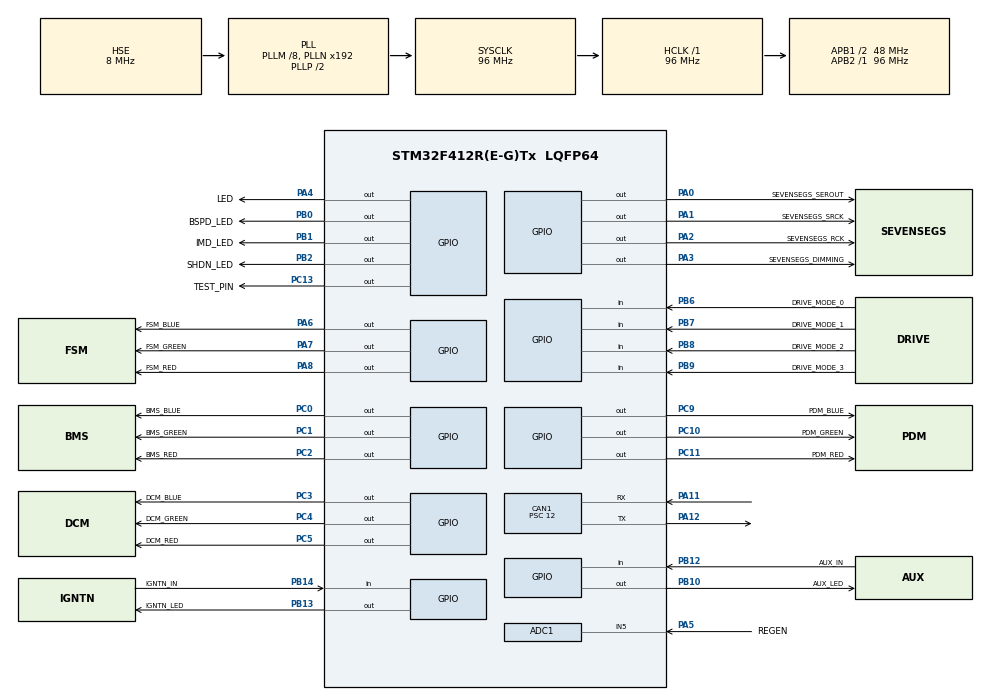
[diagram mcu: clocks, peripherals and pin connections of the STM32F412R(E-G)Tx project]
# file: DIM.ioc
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ADC1.Channel-0\#ChannelRegularConversion=ADC_CHANNEL_5
ADC1.NbrOfConversionFlag=1
ADC1.Rank-0\#ChannelRegularConversion=1
ADC1.SamplingTime-0\#ChannelRegularConversion=ADC_SAMPLETIME_3CYCLES
ADC1.master=1
CAN1.ABOM=ENABLE
CAN1.BS1=CAN_BS1_6TQ
CAN1.CalculateTimeQuantum=250.0
CAN1.NART=ENABLE
CAN1.Prescaler=12
CAN1.RFLM=ENABLE
CAN1.SJW=CAN_SJW_4TQ
CAN1.TXFP=ENABLE
Dma.ADC1.0.Direction=DMA_PERIPH_TO_MEMORY
Dma.ADC1.0.FIFOMode=DMA_FIFOMODE_DISABLE
Dma.ADC1.0.Instance=DMA2_Stream0
Dma.ADC1.0.MemDataAlignment=DMA_MDATAALIGN_HALFWORD
Dma.ADC1.0.MemInc=DMA_MINC_ENABLE
Dma.ADC1.0.Mode=DMA_NORMAL
Dma.ADC1.0.PeriphDataAlignment=DMA_PDATAALIGN_HALFWORD
Dma.ADC1.0.PeriphInc=DMA_PINC_DISABLE
Dma.ADC1.0.Priority=DMA_PRIORITY_LOW
Dma.Request0=ADC1
FREERTOS.INCLUDE_vTaskDelayUntil=1
FREERTOS.MEMORY_ALLOCATION=1
FREERTOS.Tasks01=Task100Hz,-1,512,RunTask100Hz,Default,NULL,Static,Task100HzBuffer,Task100HzControlBlock;TaskCanRx,-3,512,RunTaskCanRx,Default,NULL,Static,TaskCanRxBuffer,TaskCanRxControlBlock;TaskCanTx,-3,512,RunTaskCanTx,Default,NULL,Static,TaskCanTxBuffer,TaskCanTxControlBlock;Task1kHz,0,512,RunTask1kHz,Default,NULL,Static,Task1kHzBuffer,Task1kHzControlBlock;Task1Hz,-2,512,RunTask1Hz,Default,NULL,Static,Task1HzBuffer,Task1HzControlBlock
FREERTOS.configCHECK_FOR_STACK_OVERFLOW=2
FREERTOS.configRECORD_STACK_HIGH_ADDRESS=0
FREERTOS.configUSE_TASK_NOTIFICATIONS=1
FREERTOS.configUSE_TICK_HOOK=1
FREERTOS.configUSE_TRACE_FACILITY=1
IWDG.Reload=LSI_FREQUENCY /  IWDG_PRESCALER / IWDG_RESET_FREQUENCY
Mcu.Family=STM32F4
Mcu.Name=STM32F412R(E-G)Tx
Mcu.Package=LQFP64
Mcu.UserConstants=LSI_FREQUENCY,32000;IWDG_PRESCALER,4;IWDG_RESET_FREQUENCY,5
NVIC.CAN1_RX0_IRQn=true\:5\:0\:false\:false\:true\:true\:true\:true
NVIC.CAN1_RX1_IRQn=true\:5\:0\:false\:false\:true\:true\:true\:true
NVIC.DMA2_Stream0_IRQn=true\:5\:0\:false\:false\:true\:true\:false\:true
NVIC.PriorityGroup=NVIC_PRIORITYGROUP_4
NVIC.TIM6_IRQn=true\:0\:0\:false\:false\:true\:false\:false\:true
NVIC.TimeBase=TIM6_IRQn
NVIC.TimeBaseIP=TIM6
PA0.GPIO_Label=SEVENSEGS_SEROUT
PA0.GPIO_Speed=GPIO_SPEED_FREQ_VERY_HIGH
PA0.PinState=GPIO_PIN_RESET
PA0.Signal=GPIO_Output
PA1.GPIO_Label=SEVENSEGS_SRCK
PA1.GPIO_Speed=GPIO_SPEED_FREQ_VERY_HIGH
PA1.PinState=GPIO_PIN_RESET
PA1.Signal=GPIO_Output
PA11.Mode=Master
PA11.Signal=CAN1_RX
PA12.Mode=Master
PA12.Signal=CAN1_TX
PA13.Mode=Trace_Asynchronous_SW
PA13.Signal=SYS_JTMS-SWDIO
PA14.Mode=Trace_Asynchronous_SW
PA14.Signal=SYS_JTCK-SWCLK
PA2.GPIO_Label=SEVENSEGS_RCK
PA2.GPIO_Speed=GPIO_SPEED_FREQ_VERY_HIGH
PA2.PinState=GPIO_PIN_RESET
PA2.Signal=GPIO_Output
PA3.GPIO_Label=SEVENSEGS_DIMMING
PA3.GPIO_Speed=GPIO_SPEED_FREQ_LOW
PA3.PinState=GPIO_PIN_RESET
PA3.Signal=GPIO_Output
PA4.GPIO_Label=LED
PA4.Signal=GPIO_Output
PA5.GPIO_Label=REGEN
PA5.Signal=SharedAnalog_PA5
PA6.GPIO_Label=FSM_BLUE
PA6.Signal=GPIO_Output
PA7.GPIO_Label=FSM_GREEN
PA7.Signal=GPIO_Output
PA8.GPIO_Label=FSM_RED
PA8.Signal=GPIO_Output
PB0.GPIO_Label=BSPD_LED
PB0.Signal=GPIO_Output
PB1.GPIO_Label=IMD_LED
PB1.Signal=GPIO_Output
PB10.GPIO_Label=AUX_LED
PB10.Signal=GPIO_Output
PB12.GPIO_Label=AUX_IN
PB12.GPIO_PuPd=GPIO_PULLUP
PB12.Signal=GPIO_Input
PB13.GPIO_Label=IGNTN_LED
PB13.Signal=GPIO_Output
PB14.GPIO_Label=IGNTN_IN
PB14.GPIO_PuPd=GPIO_PULLUP
PB14.Signal=GPIO_Input
PB2.GPIO_Label=SHDN_LED
PB2.Signal=GPIO_Output
PB3.Mode=Trace_Asynchronous_SW
PB3.Signal=SYS_JTDO-SWO
PB6.GPIO_Label=DRIVE_MODE_0
PB6.Signal=GPIO_Input
PB7.GPIO_Label=DRIVE_MODE_1
PB7.Signal=GPIO_Input
PB8.GPIO_Label=DRIVE_MODE_2
PB8.Signal=GPIO_Input
PB9.GPIO_Label=DRIVE_MODE_3
PB9.Signal=GPIO_Input
PC0.GPIO_Label=BMS_BLUE
PC0.Signal=GPIO_Output
PC1.GPIO_Label=BMS_GREEN
PC1.Signal=GPIO_Output
PC10.GPIO_Label=PDM_GREEN
PC10.Signal=GPIO_Output
PC11.GPIO_Label=PDM_RED
PC11.Signal=GPIO_Output
PC13.GPIO_Label=TEST_PIN
PC13.PinState=GPIO_PIN_SET
PC13.Signal=GPIO_Output
PC2.GPIO_Label=BMS_RED
PC2.Signal=GPIO_Output
PC3.GPIO_Label=DCM_BLUE
PC3.Signal=GPIO_Output
PC4.GPIO_Label=DCM_GREEN
PC4.Signal=GPIO_Output
PC5.GPIO_Label=DCM_RED
PC5.Signal=GPIO_Output
PC9.GPIO_Label=PDM_BLUE
PC9.Signal=GPIO_Output
PH0\ -\ OSC_IN.Mode=HSE-External-Oscillator
PH0\ -\ OSC_IN.Signal=RCC_OSC_IN
PH1\ -\ OSC_OUT.Mode=HSE-External-Oscillator
PH1\ -\ OSC_OUT.Signal=RCC_OSC_OUT
ProjectManager.HeapSize=0X00
ProjectManager.StackSize=0x400
ProjectManager.TargetToolchain=SW4STM32
RCC.AHBFreq_Value=96000000
RCC.APB1CLKDivider=RCC_HCLK_DIV2
RCC.APB1Freq_Value=48000000
RCC.APB1TimFreq_Value=96000000
RCC.APB2Freq_Value=96000000
RCC.APB2TimFreq_Value=96000000
RCC.CortexFreq_Value=96000000
RCC.HCLKFreq_Value=96000000
RCC.HSE_VALUE=8000000
RCC.PLLM=8
RCC.PLLSourceVirtual=RCC_PLLSOURCE_HSE
RCC.SYSCLKFreq_VALUE=96000000
RCC.SYSCLKSource=RCC_SYSCLKSOURCE_PLLCLK
RCC.USBFreq_Value=96000000
RCC.VCOOutputFreq_Value=192000000
SH.SharedAnalog_PA5.0=GPIO_Analog
SH.SharedAnalog_PA5.1=ADC1_IN5,IN5
VP_FREERTOS_VS_CMSIS_V1.Mode=CMSIS_V1
VP_IWDG_VS_IWDG.Mode=IWDG_Activate
VP_SYS_VS_tim6.Mode=TIM6
board=custom

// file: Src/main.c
/* USER CODE BEGIN Header */
/**
 ******************************************************************************
 * @file           : main.c
 * @brief          : Main program body
 ******************************************************************************
 * @attention
 *
 * <h2><center>&copy; Copyright (c) 2020 STMicroelectronics.
 * All rights reserved.</center></h2>
 *
 * This software component is licensed by ST under BSD 3-Clause license,
 * the "License"; You may not use this file except in compliance with the
 * License. You may obtain a copy of the License at:
 *                        opensource.org/licenses/BSD-3-Clause
 *
 ******************************************************************************
 */
/* USER CODE END Header */

#include "main.h"
#include "cmsis_os.h"

/* USER CODE BEGIN Includes */
#include <assert.h>

#include "App_DimWorld.h"
#include "App_SharedMacros.h"
#include "App_SevenSegDisplay.h"
#include "App_SharedStateMachine.h"
#include "states/App_DriveState.h"
#include "configs/App_RotarySwitchConfig.h"
#include "configs/App_HeartbeatMonitorConfig.h"
#include "App_CanAlerts.h"

#include "Io_CanTx.h"
#include "Io_CanRx.h"
#include "Io_SoftwareWatchdog.h"
#include "Io_StackWaterMark.h"
#include "Io_SevenSegDisplays.h"
#include "Io_SharedCan.h"
#include "Io_SharedErrorHandlerOverride.h"
#include "Io_SharedHardFaultHandler.h"
#include "Io_SharedHeartbeatMonitor.h"
#include "Io_RgbLedSequence.h"
#include "Io_DriveModeSwitch.h"
#include "Io_Leds.h"
#include "Io_Switches.h"
#include "Io_Adc.h"
#include "Io_RgbLeds.h"
/* USER CODE END Includes */

ADC_HandleTypeDef hadc1;
DMA_HandleTypeDef hdma_adc1;

CAN_HandleTypeDef hcan1;

IWDG_HandleTypeDef hiwdg;

osThreadId          Task100HzHandle;
uint32_t            Task100HzBuffer[512];
osStaticThreadDef_t Task100HzControlBlock;
osThreadId          TaskCanRxHandle;
uint32_t            TaskCanRxBuffer[512];
osStaticThreadDef_t TaskCanRxControlBlock;
osThreadId          TaskCanTxHandle;
uint32_t            TaskCanTxBuffer[512];
osStaticThreadDef_t TaskCanTxControlBlock;
osThreadId          Task1kHzHandle;
uint32_t            Task1kHzBuffer[512];
osStaticThreadDef_t Task1kHzControlBlock;
osThreadId          Task1HzHandle;
uint32_t            Task1HzBuffer[512];
osStaticThreadDef_t Task1HzControlBlock;
/* USER CODE BEGIN PV */
struct DimWorld *         world;
struct StateMachine *     state_machine;
struct DimCanTxInterface *can_tx;
struct DimCanRxInterface *can_rx;
struct SevenSegDisplay *  left_seven_seg_display;
struct SevenSegDisplay *  middle_seven_seg_display;
struct SevenSegDisplay *  right_seven_seg_display;
struct SevenSegDisplays * seven_seg_displays;
struct HeartbeatMonitor * heartbeat_monitor;
struct RgbLedSequence *   rgb_led_sequence;
struct RotarySwitch *     drive_mode_switch;
struct Led *              imd_led;
struct Led *              bspd_led;
struct BinarySwitch *     start_switch;
struct BinarySwitch *     aux_switch;
struct RgbLed *           bms_status_led;
struct RgbLed *           dcm_status_led;
struct RgbLed *           dim_status_led;
struct RgbLed *           fsm_status_led;
struct RgbLed *           pdm_status_led;
struct Clock *            clock;
/* USER CODE END PV */

void        SystemClock_Config(void);
static void MX_GPIO_Init(void);
static void MX_DMA_Init(void);
static void MX_ADC1_Init(void);
static void MX_CAN1_Init(void);
static void MX_IWDG_Init(void);
void        RunTask100Hz(void const *argument);
void        RunTaskCanRx(void const *argument);
void        RunTaskCanTx(void const *argument);
void        RunTask1kHz(void const *argument);
void        RunTask1Hz(void const *argument);

/* USER CODE BEGIN 0 */
static void CanRxQueueOverflowCallBack(size_t overflow_count)
{
    App_CanTx_DIM_Errors_RxOverflowCount_Set(overflow_count);
}

static void CanTxQueueOverflowCallBack(size_t overflow_count)
{
    App_CanTx_DIM_Errors_TxOverflowCount_Set(overflow_count);
}
/* USER CODE END 0 */

int main(void)
{

    /* MCU Configuration--------------------------------------------------------*/

    /* Reset of all peripherals, Initializes the Flash interface and the Systick. */
    HAL_Init();

    /* Configure the system clock */
    SystemClock_Config();

    /* Initialize all configured peripherals */
    MX_GPIO_Init();
    MX_DMA_Init();
    MX_ADC1_Init();
    MX_CAN1_Init();
    MX_IWDG_Init();
    /* USER CODE BEGIN 2 */
    __HAL_DBGMCU_FREEZE_IWDG();

    HAL_ADC_Start_DMA(&hadc1, (uint32_t *)Io_Adc_GetRawAdcValues(), hadc1.Init.NbrOfConversion);
    //    HAL_TIM_Base_Start(&htim2); // TODO: May need to enable this for DMA for ADC

    Io_SharedHardFaultHandler_Init();
    Io_SharedSoftwareWatchdog_Init(Io_HardwareWatchdog_Refresh, Io_SoftwareWatchdog_TimeoutCallback);
    Io_SharedCan_Init(&hcan1, CanTxQueueOverflowCallBack, CanRxQueueOverflowCallBack);
    Io_CanTx_EnableMode(CAN_MODE_DEFAULT, true);
    Io_SevenSegDisplays_Init();

    App_CanTx_Init();
    App_CanRx_Init();
    App_CanAlerts_Init(Io_CanTx_DIM_Alerts_SendAperiodic);

    left_seven_seg_display   = App_SevenSegDisplay_Create(Io_SevenSegDisplays_SetLeftHexDigit);
    middle_seven_seg_display = App_SevenSegDisplay_Create(Io_SevenSegDisplays_SetMiddleHexDigit);
    right_seven_seg_display  = App_SevenSegDisplay_Create(Io_SevenSegDisplays_SetRightHexDigit);

    seven_seg_displays = App_SevenSegDisplays_Create(
        left_seven_seg_display, middle_seven_seg_display, right_seven_seg_display, Io_SevenSegDisplays_WriteCommands);

    heartbeat_monitor = App_SharedHeartbeatMonitor_Create(
        Io_SharedHeartbeatMonitor_GetCurrentMs, HEARTBEAT_MONITOR_TIMEOUT_PERIOD_MS, HEARTBEAT_MONITOR_BOARDS_TO_CHECK);

    rgb_led_sequence = App_SharedRgbLedSequence_Create(
        Io_RgbLedSequence_TurnOnRedLed, Io_RgbLedSequence_TurnOnBlueLed, Io_RgbLedSequence_TurnOnGreenLed);

    drive_mode_switch = App_RotarySwitch_Create(Io_DriveModeSwitch_GetPosition, NUM_DRIVE_MODE_SWITCH_POSITIONS);

    imd_led = App_Led_Create(Io_Leds_TurnOnImdLed, Io_Leds_TurnOffImdLed);

    bspd_led = App_Led_Create(Io_Leds_TurnOnBspdLed, Io_Leds_TurnOffBspdLed);

    start_switch = App_BinarySwitch_Create(Io_Switches_StartSwitchIsTurnedOn);

    aux_switch = App_BinarySwitch_Create(Io_Switches_AuxSwitchIsTurnedOn);

    bms_status_led = App_SharedRgbLed_Create(
        Io_RgbLeds_TurnBmsStatusLedRed, Io_RgbLeds_TurnBmsStatusLedGreen, Io_RgbLeds_TurnBmsStatusLedBlue,
        Io_RgbLeds_TurnOffBmsStatusLed);

    dcm_status_led = App_SharedRgbLed_Create(
        Io_RgbLeds_TurnDcmStatusLedRed, Io_RgbLeds_TurnDcmStatusLedGreen, Io_RgbLeds_TurnDcmStatusLedBlue,
        Io_RgbLeds_TurnOffDcmStatusLed);

    dim_status_led = App_SharedRgbLed_Create(
        Io_RgbLeds_TurnDimStatusLedRed, Io_RgbLeds_TurnDimStatusLedGreen, Io_RgbLeds_TurnDimStatusLedBlue,
        Io_RgbLeds_TurnOffDimStatusLed);

    fsm_status_led = App_SharedRgbLed_Create(
        Io_RgbLeds_TurnFsmStatusLedRed, Io_RgbLeds_TurnFsmStatusLedGreen, Io_RgbLeds_TurnFsmStatusLedBlue,
        Io_RgbLeds_TurnOffFsmStatusLed);

    pdm_status_led = App_SharedRgbLed_Create(
        Io_RgbLeds_TurnPdmStatusLedRed, Io_RgbLeds_TurnPdmStatusLedGreen, Io_RgbLeds_TurnPdmStatusLedBlue,
        Io_RgbLeds_TurnOffPdmStatusLed);

    clock = App_SharedClock_Create();

    world = App_DimWorld_Create(
        seven_seg_displays, heartbeat_monitor, rgb_led_sequence, drive_mode_switch, imd_led, bspd_led, start_switch,
        aux_switch, bms_status_led, dcm_status_led, dim_status_led, fsm_status_led, pdm_status_led, clock);

    state_machine = App_SharedStateMachine_Create(world, App_GetDriveState());

    App_CanAlerts_SetAlert(DIM_ALERT_STARTUP, true);
    /* USER CODE END 2 */

    /* Create the thread(s) */
    /* definition and creation of Task100Hz */
    osThreadStaticDef(Task100Hz, RunTask100Hz, osPriorityBelowNormal, 0, 512, Task100HzBuffer, &Task100HzControlBlock);
    Task100HzHandle = osThreadCreate(osThread(Task100Hz), NULL);

    /* definition and creation of TaskCanRx */
    osThreadStaticDef(TaskCanRx, RunTaskCanRx, osPriorityIdle, 0, 512, TaskCanRxBuffer, &TaskCanRxControlBlock);
    TaskCanRxHandle = osThreadCreate(osThread(TaskCanRx), NULL);

    /* definition and creation of TaskCanTx */
    osThreadStaticDef(TaskCanTx, RunTaskCanTx, osPriorityIdle, 0, 512, TaskCanTxBuffer, &TaskCanTxControlBlock);
    TaskCanTxHandle = osThreadCreate(osThread(TaskCanTx), NULL);

    /* definition and creation of Task1kHz */
    osThreadStaticDef(Task1kHz, RunTask1kHz, osPriorityNormal, 0, 512, Task1kHzBuffer, &Task1kHzControlBlock);
    Task1kHzHandle = osThreadCreate(osThread(Task1kHz), NULL);

    /* definition and creation of Task1Hz */
    osThreadStaticDef(Task1Hz, RunTask1Hz, osPriorityLow, 0, 512, Task1HzBuffer, &Task1HzControlBlock);
    Task1HzHandle = osThreadCreate(osThread(Task1Hz), NULL);

    /* USER CODE BEGIN RTOS_THREADS */
    // According to Percpio documentation, vTraceEnable() should be the last
    // function call before the scheduler starts.
#if (configUSE_TRACE_FACILITY == 1)
    vTraceEnable(TRC_INIT);
#endif
    /* USER CODE END RTOS_THREADS */

    /* Start scheduler */
    osKernelStart();

    /* We should never get here as control is now taken by the scheduler */

    /* Infinite loop */
    while (1)
    {

    }
}

void SystemClock_Config(void)
{
    RCC_OscInitTypeDef RCC_OscInitStruct = { 0 };
    RCC_ClkInitTypeDef RCC_ClkInitStruct = { 0 };

    /** Configure the main internal regulator output voltage
     */
    __HAL_RCC_PWR_CLK_ENABLE();
    __HAL_PWR_VOLTAGESCALING_CONFIG(PWR_REGULATOR_VOLTAGE_SCALE1);
    /** Initializes the CPU, AHB and APB busses clocks
     */
    RCC_OscInitStruct.OscillatorType = RCC_OSCILLATORTYPE_LSI | RCC_OSCILLATORTYPE_HSE;
    RCC_OscInitStruct.HSEState       = RCC_HSE_ON;
    RCC_OscInitStruct.LSIState       = RCC_LSI_ON;
    RCC_OscInitStruct.PLL.PLLState   = RCC_PLL_ON;
    RCC_OscInitStruct.PLL.PLLSource  = RCC_PLLSOURCE_HSE;
    RCC_OscInitStruct.PLL.PLLM       = 8;
    RCC_OscInitStruct.PLL.PLLN       = 192;
    RCC_OscInitStruct.PLL.PLLP       = RCC_PLLP_DIV2;
    RCC_OscInitStruct.PLL.PLLQ       = 2;
    RCC_OscInitStruct.PLL.PLLR       = 2;
    if (HAL_RCC_OscConfig(&RCC_OscInitStruct) != HAL_OK)
    {
        Error_Handler();
    }
    /** Initializes the CPU, AHB and APB busses clocks
     */
    RCC_ClkInitStruct.ClockType = RCC_CLOCKTYPE_HCLK | RCC_CLOCKTYPE_SYSCLK | RCC_CLOCKTYPE_PCLK1 | RCC_CLOCKTYPE_PCLK2;
    RCC_ClkInitStruct.SYSCLKSource   = RCC_SYSCLKSOURCE_PLLCLK;
    RCC_ClkInitStruct.AHBCLKDivider  = RCC_SYSCLK_DIV1;
    RCC_ClkInitStruct.APB1CLKDivider = RCC_HCLK_DIV2;
    RCC_ClkInitStruct.APB2CLKDivider = RCC_HCLK_DIV1;

    if (HAL_RCC_ClockConfig(&RCC_ClkInitStruct, FLASH_LATENCY_3) != HAL_OK)
    {
        Error_Handler();
    }
}

static void MX_ADC1_Init(void)
{

    ADC_ChannelConfTypeDef sConfig = { 0 };

    /** Configure the global features of the ADC (Clock, Resolution, Data Alignment and number of conversion)
     */
    hadc1.Instance                   = ADC1;
    hadc1.Init.ClockPrescaler        = ADC_CLOCK_SYNC_PCLK_DIV4;
    hadc1.Init.Resolution            = ADC_RESOLUTION_12B;
    hadc1.Init.ScanConvMode          = DISABLE;
    hadc1.Init.ContinuousConvMode    = DISABLE;
    hadc1.Init.DiscontinuousConvMode = DISABLE;
    hadc1.Init.ExternalTrigConvEdge  = ADC_EXTERNALTRIGCONVEDGE_NONE;
    hadc1.Init.ExternalTrigConv      = ADC_SOFTWARE_START;
    hadc1.Init.DataAlign             = ADC_DATAALIGN_RIGHT;
    hadc1.Init.NbrOfConversion       = 1;
    hadc1.Init.DMAContinuousRequests = DISABLE;
    hadc1.Init.EOCSelection          = ADC_EOC_SINGLE_CONV;
    if (HAL_ADC_Init(&hadc1) != HAL_OK)
    {
        Error_Handler();
    }
    /** Configure for the selected ADC regular channel its corresponding rank in the sequencer and its sample time.
     */
    sConfig.Channel      = ADC_CHANNEL_5;
    sConfig.Rank         = 1;
    sConfig.SamplingTime = ADC_SAMPLETIME_3CYCLES;
    if (HAL_ADC_ConfigChannel(&hadc1, &sConfig) != HAL_OK)
    {
        Error_Handler();
    }
}

static void MX_CAN1_Init(void)
{

    hcan1.Instance                  = CAN1;
    hcan1.Init.Prescaler            = 12;
    hcan1.Init.Mode                 = CAN_MODE_NORMAL;
    hcan1.Init.SyncJumpWidth        = CAN_SJW_4TQ;
    hcan1.Init.TimeSeg1             = CAN_BS1_6TQ;
    hcan1.Init.TimeSeg2             = CAN_BS2_1TQ;
    hcan1.Init.TimeTriggeredMode    = DISABLE;
    hcan1.Init.AutoBusOff           = ENABLE;
    hcan1.Init.AutoWakeUp           = DISABLE;
    hcan1.Init.AutoRetransmission   = ENABLE;
    hcan1.Init.ReceiveFifoLocked    = ENABLE;
    hcan1.Init.TransmitFifoPriority = ENABLE;
    if (HAL_CAN_Init(&hcan1) != HAL_OK)
    {
        Error_Handler();
    }
}

static void MX_IWDG_Init(void)
{

    hiwdg.Instance       = IWDG;
    hiwdg.Init.Prescaler = IWDG_PRESCALER_4;
    hiwdg.Init.Reload    = LSI_FREQUENCY / IWDG_PRESCALER / IWDG_RESET_FREQUENCY;
    if (HAL_IWDG_Init(&hiwdg) != HAL_OK)
    {
        Error_Handler();
    }
}

static void MX_DMA_Init(void)
{
    /* DMA controller clock enable */
    __HAL_RCC_DMA2_CLK_ENABLE();

    /* DMA interrupt init */
    /* DMA2_Stream0_IRQn interrupt configuration */
    HAL_NVIC_SetPriority(DMA2_Stream0_IRQn, 5, 0);
    HAL_NVIC_EnableIRQ(DMA2_Stream0_IRQn);
}

static void MX_GPIO_Init(void)
{
    GPIO_InitTypeDef GPIO_InitStruct = { 0 };

    /* GPIO Ports Clock Enable */
    __HAL_RCC_GPIOC_CLK_ENABLE();
    __HAL_RCC_GPIOH_CLK_ENABLE();
    __HAL_RCC_GPIOA_CLK_ENABLE();
    __HAL_RCC_GPIOB_CLK_ENABLE();

    /*Configure GPIO pin Output Level */
    HAL_GPIO_WritePin(TEST_PIN_GPIO_Port, TEST_PIN_Pin, GPIO_PIN_SET);

    /*Configure GPIO pin Output Level */
    HAL_GPIO_WritePin(
        GPIOC,
        BMS_BLUE_Pin | BMS_GREEN_Pin | BMS_RED_Pin | DCM_BLUE_Pin | DCM_GREEN_Pin | DCM_RED_Pin | DIM_BLUE_Pin |
            DIM_GREEN_Pin | DIM_RED_Pin | PDM_BLUE_Pin | PDM_GREEN_Pin | PDM_RED_Pin,
        GPIO_PIN_RESET);

    /*Configure GPIO pin Output Level */
    HAL_GPIO_WritePin(
        GPIOA,
        SEVENSEGS_SEROUT_Pin | SEVENSEGS_SRCK_Pin | SEVENSEGS_RCK_Pin | SEVENSEGS_DIMMING_Pin | LED_Pin | FSM_BLUE_Pin |
            FSM_GREEN_Pin | FSM_RED_Pin,
        GPIO_PIN_RESET);

    /*Configure GPIO pin Output Level */
    HAL_GPIO_WritePin(GPIOB, IMD_LED_Pin | BSPD_LED_Pin | SHDN_LED_Pin | AUX_LED_Pin | IGNTN_LED_Pin, GPIO_PIN_RESET);

    /*Configure GPIO pins : TEST_PIN_Pin BMS_BLUE_Pin BMS_GREEN_Pin BMS_RED_Pin
                             DCM_BLUE_Pin DCM_GREEN_Pin DCM_RED_Pin DIM_BLUE_Pin
                             DIM_GREEN_Pin DIM_RED_Pin PDM_BLUE_Pin PDM_GREEN_Pin
                             PDM_RED_Pin */
    GPIO_InitStruct.Pin = TEST_PIN_Pin | BMS_BLUE_Pin | BMS_GREEN_Pin | BMS_RED_Pin | DCM_BLUE_Pin | DCM_GREEN_Pin |
                          DCM_RED_Pin | DIM_BLUE_Pin | DIM_GREEN_Pin | DIM_RED_Pin | PDM_BLUE_Pin | PDM_GREEN_Pin |
                          PDM_RED_Pin;
    GPIO_InitStruct.Mode  = GPIO_MODE_OUTPUT_PP;
    GPIO_InitStruct.Pull  = GPIO_NOPULL;
    GPIO_InitStruct.Speed = GPIO_SPEED_FREQ_LOW;
    HAL_GPIO_Init(GPIOC, &GPIO_InitStruct);

    /*Configure GPIO pins : SEVENSEGS_SEROUT_Pin SEVENSEGS_SRCK_Pin SEVENSEGS_RCK_Pin */
    GPIO_InitStruct.Pin   = SEVENSEGS_SEROUT_Pin | SEVENSEGS_SRCK_Pin | SEVENSEGS_RCK_Pin;
    GPIO_InitStruct.Mode  = GPIO_MODE_OUTPUT_PP;
    GPIO_InitStruct.Pull  = GPIO_NOPULL;
    GPIO_InitStruct.Speed = GPIO_SPEED_FREQ_VERY_HIGH;
    HAL_GPIO_Init(GPIOA, &GPIO_InitStruct);

    /*Configure GPIO pins : SEVENSEGS_DIMMING_Pin LED_Pin FSM_BLUE_Pin FSM_GREEN_Pin
                             FSM_RED_Pin */
    GPIO_InitStruct.Pin   = SEVENSEGS_DIMMING_Pin | LED_Pin | FSM_BLUE_Pin | FSM_GREEN_Pin | FSM_RED_Pin;
    GPIO_InitStruct.Mode  = GPIO_MODE_OUTPUT_PP;
    GPIO_InitStruct.Pull  = GPIO_NOPULL;
    GPIO_InitStruct.Speed = GPIO_SPEED_FREQ_LOW;
    HAL_GPIO_Init(GPIOA, &GPIO_InitStruct);

    /*Configure GPIO pin : REGEN_Pin */
    GPIO_InitStruct.Pin  = REGEN_Pin;
    GPIO_InitStruct.Mode = GPIO_MODE_ANALOG;
    GPIO_InitStruct.Pull = GPIO_NOPULL;
    HAL_GPIO_Init(REGEN_GPIO_Port, &GPIO_InitStruct);

    /*Configure GPIO pins : IMD_LED_Pin BSPD_LED_Pin SHDN_LED_Pin AUX_LED_Pin
                             IGNTN_LED_Pin */
    GPIO_InitStruct.Pin   = IMD_LED_Pin | BSPD_LED_Pin | SHDN_LED_Pin | AUX_LED_Pin | IGNTN_LED_Pin;
    GPIO_InitStruct.Mode  = GPIO_MODE_OUTPUT_PP;
    GPIO_InitStruct.Pull  = GPIO_NOPULL;
    GPIO_InitStruct.Speed = GPIO_SPEED_FREQ_LOW;
    HAL_GPIO_Init(GPIOB, &GPIO_InitStruct);

    /*Configure GPIO pins : AUX_IN_Pin IGNTN_IN_Pin */
    GPIO_InitStruct.Pin  = AUX_IN_Pin | IGNTN_IN_Pin;
    GPIO_InitStruct.Mode = GPIO_MODE_INPUT;
    GPIO_InitStruct.Pull = GPIO_PULLUP;
    HAL_GPIO_Init(GPIOB, &GPIO_InitStruct);

    /*Configure GPIO pins : DRIVE_MODE_0_Pin DRIVE_MODE_1_Pin DRIVE_MODE_2_Pin DRIVE_MODE_3_Pin */
    GPIO_InitStruct.Pin  = DRIVE_MODE_0_Pin | DRIVE_MODE_1_Pin | DRIVE_MODE_2_Pin | DRIVE_MODE_3_Pin;
    GPIO_InitStruct.Mode = GPIO_MODE_INPUT;
    GPIO_InitStruct.Pull = GPIO_NOPULL;
    HAL_GPIO_Init(GPIOB, &GPIO_InitStruct);
}

void RunTask100Hz(void const *argument)
{
    /* USER CODE BEGIN 5 */
    UNUSED(argument);
    uint32_t                 PreviousWakeTime = osKernelSysTick();
    static const TickType_t  period_ms        = 10;
    SoftwareWatchdogHandle_t watchdog         = Io_SharedSoftwareWatchdog_AllocateWatchdog();
    Io_SharedSoftwareWatchdog_InitWatchdog(watchdog, RTOS_TASK_100HZ, period_ms);

    /* Infinite loop */
    for (;;)
    {
        App_SharedStateMachine_Tick100Hz(state_machine);
        Io_CanTx_Enqueue100HzMsgs();

        // Watchdog check-in must be the last function called before putting the
        // task to sleep.
        Io_SharedSoftwareWatchdog_CheckInWatchdog(watchdog);
        osDelayUntil(&PreviousWakeTime, period_ms);
    }
    /* USER CODE END 5 */
}

void RunTaskCanRx(void const *argument)
{
    /* USER CODE BEGIN RunTaskCanRx */
    UNUSED(argument);

    /* Infinite loop */
    for (;;)
    {
        struct CanMsg message;
        Io_SharedCan_DequeueCanRxMessage(&message);
        Io_CanRx_UpdateRxTableWithMessage(&message);
    }
    /* USER CODE END RunTaskCanRx */
}

void RunTaskCanTx(void const *argument)
{
    /* USER CODE BEGIN RunTaskCanTx */
    UNUSED(argument);

    /* Infinite loop */
    for (;;)
    {
        Io_SharedCan_TransmitEnqueuedCanTxMessagesFromTask();
    }
    /* USER CODE END RunTaskCanTx */
}

void RunTask1kHz(void const *argument)
{
    /* USER CODE BEGIN RunTask1kHz */
    UNUSED(argument);
    uint32_t                 PreviousWakeTime = osKernelSysTick();
    static const TickType_t  period_ms        = 1;
    SoftwareWatchdogHandle_t watchdog         = Io_SharedSoftwareWatchdog_AllocateWatchdog();
    Io_SharedSoftwareWatchdog_InitWatchdog(watchdog, RTOS_TASK_1KHZ, period_ms);

    /* Infinite loop */
    for (;;)
    {
        // Check in for timeouts for all RTOS tasks
        Io_SharedSoftwareWatchdog_CheckForTimeouts();
        const uint32_t task_start_ms = TICK_TO_MS(osKernelSysTick());

        App_SharedClock_SetCurrentTimeInMilliseconds(clock, task_start_ms);
        Io_CanTx_EnqueueOtherPeriodicMsgs(task_start_ms);

        // Watchdog check-in must be the last function called before putting the
        // task to sleep. Prevent check in if the elapsed period is greater or
        // equal to the period ms
        if ((TICK_TO_MS(osKernelSysTick()) - task_start_ms) <= period_ms)
        {
            Io_SharedSoftwareWatchdog_CheckInWatchdog(watchdog);
        }

        osDelayUntil(&PreviousWakeTime, period_ms);
    }
    /* USER CODE END RunTask1kHz */
}

void RunTask1Hz(void const *argument)
{
    /* USER CODE BEGIN RunTask1Hz */
    UNUSED(argument);
    uint32_t                 PreviousWakeTime = osKernelSysTick();
    static const TickType_t  period_ms        = 1000U;
    SoftwareWatchdogHandle_t watchdog         = Io_SharedSoftwareWatchdog_AllocateWatchdog();
    Io_SharedSoftwareWatchdog_InitWatchdog(watchdog, RTOS_TASK_1HZ, period_ms);

    /* Infinite loop */
    for (;;)
    {
        Io_StackWaterMark_Check();
        App_SharedStateMachine_Tick1Hz(state_machine);

        const bool debug_mode_enabled = App_CanRx_Debug_CanModes_EnableDebugMode_Get();
        Io_CanTx_EnableMode(CAN_MODE_DEBUG, debug_mode_enabled);
        Io_CanTx_Enqueue1HzMsgs();

        // Watchdog check-in must be the last function called before putting the
        // task to sleep.
        Io_SharedSoftwareWatchdog_CheckInWatchdog(watchdog);
        osDelayUntil(&PreviousWakeTime, period_ms);
    }
    /* USER CODE END RunTask1Hz */
}

void HAL_TIM_PeriodElapsedCallback(TIM_HandleTypeDef *htim)
{
    if (htim->Instance == TIM6)
    {
        HAL_IncTick();
    }
}

void Error_Handler(void)
{
    /* USER CODE BEGIN Error_Handler_Debug */
    __assert_func(__FILE__, __LINE__, "Error_Handler", "Error_Handler");
    /* USER CODE END Error_Handler_Debug */
}

#ifdef USE_FULL_ASSERT
/**
 * @brief  Reports the name of the source file and the source line number
 *         where the assert_param error has occurred.
 * @param  file: pointer to the source file name
 * @param  line: assert_param error line source number
 * @retval None
 */
void assert_failed(uint8_t *file, uint32_t line)
{
    /* USER CODE BEGIN 6 */
    __assert_func(file, line, "assert_failed", "assert_failed");
    /* USER CODE END 6 */
}
#endif /* USE_FULL_ASSERT */

/************************ (C) COPYRIGHT STMicroelectronics *****END OF FILE****/

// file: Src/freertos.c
/* USER CODE BEGIN Header */
/**
 ******************************************************************************
 * File Name          : freertos.c
 * Description        : Code for freertos applications
 ******************************************************************************
 * @attention
 *
 * <h2><center>&copy; Copyright (c) 2023 STMicroelectronics.
 * All rights reserved.</center></h2>
 *
 * This software component is licensed by ST under Ultimate Liberty license
 * SLA0044, the "License"; You may not use this file except in compliance with
 * the License. You may obtain a copy of the License at:
 *                             www.st.com/SLA0044
 *
 ******************************************************************************
 */
/* USER CODE END Header */

#include "FreeRTOS.h"

#include "main.h"
#include "task.h"

/* GetIdleTaskMemory prototype (linked to static allocation support) */
void vApplicationGetIdleTaskMemory(StaticTask_t **ppxIdleTaskTCBBuffer,
                                   StackType_t **ppxIdleTaskStackBuffer,
                                   uint32_t *pulIdleTaskStackSize);

/* Hook prototypes */
void vApplicationTickHook(void);
void vApplicationStackOverflowHook(xTaskHandle xTask, signed char *pcTaskName);

/* USER CODE BEGIN 3 */
__weak void vApplicationTickHook(void) {
  /* This function will be called by each tick interrupt if
  configUSE_TICK_HOOK is set to 1 in FreeRTOSConfig.h. User code can be
  added here, but the tick hook is called from an interrupt context, so
  code must not attempt to block, and only the interrupt safe FreeRTOS API
  functions can be used (those that end in FromISR()). */
}
/* USER CODE END 3 */

/* USER CODE BEGIN 4 */
__weak void vApplicationStackOverflowHook(xTaskHandle xTask,
                                          signed char *pcTaskName) {
  /* Run time stack overflow checking is performed if
  configCHECK_FOR_STACK_OVERFLOW is defined to 1 or 2. This hook function is
  called if a stack overflow is detected. */
}
/* USER CODE END 4 */

/* USER CODE BEGIN GET_IDLE_TASK_MEMORY */
static StaticTask_t xIdleTaskTCBBuffer;
static StackType_t xIdleStack[configMINIMAL_STACK_SIZE];

void vApplicationGetIdleTaskMemory(StaticTask_t **ppxIdleTaskTCBBuffer,
                                   StackType_t **ppxIdleTaskStackBuffer,
                                   uint32_t *pulIdleTaskStackSize) {
  *ppxIdleTaskTCBBuffer = &xIdleTaskTCBBuffer;
  *ppxIdleTaskStackBuffer = &xIdleStack[0];
  *pulIdleTaskStackSize = configMINIMAL_STACK_SIZE;
  /* place for user code */
}
/* USER CODE END GET_IDLE_TASK_MEMORY */

/************************ (C) COPYRIGHT STMicroelectronics *****END OF FILE****/
